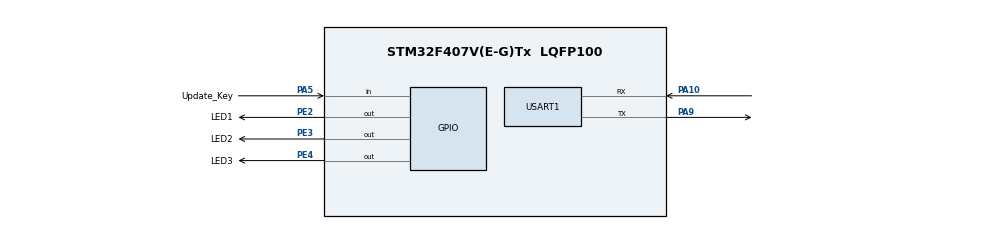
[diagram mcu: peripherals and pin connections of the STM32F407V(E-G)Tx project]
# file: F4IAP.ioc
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Mcu.Family=STM32F4
Mcu.Name=STM32F407V(E-G)Tx
Mcu.Package=LQFP100
NVIC.PriorityGroup=NVIC_PRIORITYGROUP_4
PA10.Mode=Asynchronous
PA10.Signal=USART1_RX
PA13.Mode=Serial_Wire
PA13.Signal=SYS_JTMS-SWDIO
PA14.Mode=Serial_Wire
PA14.Signal=SYS_JTCK-SWCLK
PA5.GPIO_Label=Update_Key
PA5.GPIO_PuPd=GPIO_PULLUP
PA5.Signal=GPIO_Input
PA9.Mode=Asynchronous
PA9.Signal=USART1_TX
PE2.GPIO_Label=LED1
PE2.GPIO_Speed=GPIO_SPEED_FREQ_HIGH
PE2.Signal=GPIO_Output
PE3.GPIO_Label=LED2
PE3.GPIO_Speed=GPIO_SPEED_FREQ_HIGH
PE3.Signal=GPIO_Output
PE4.GPIO_Label=LED3
PE4.GPIO_Speed=GPIO_SPEED_FREQ_HIGH
PE4.Signal=GPIO_Output
PH0-OSC_IN.Mode=HSE-External-Oscillator
PH0-OSC_IN.Signal=RCC_OSC_IN
PH1-OSC_OUT.Mode=HSE-External-Oscillator
PH1-OSC_OUT.Signal=RCC_OSC_OUT
ProjectManager.HeapSize=0x200
ProjectManager.StackSize=0x400
ProjectManager.TargetToolchain=MDK-ARM V5
RCC.48MHZClocksFreq_Value=84000000
RCC.AHBFreq_Value=168000000
RCC.APB1CLKDivider=RCC_HCLK_DIV4
RCC.APB1Freq_Value=42000000
RCC.APB1TimFreq_Value=84000000
RCC.APB2CLKDivider=RCC_HCLK_DIV2
RCC.APB2Freq_Value=84000000
RCC.APB2TimFreq_Value=168000000
RCC.CortexFreq_Value=168000000
RCC.HCLKFreq_Value=168000000
RCC.HSE_VALUE=25000000
RCC.HSI_VALUE=16000000
RCC.LSE_VALUE=32768
RCC.PLLM=25
RCC.PLLN=336
RCC.PLLSourceVirtual=RCC_PLLSOURCE_HSE
RCC.SYSCLKFreq_VALUE=168000000
RCC.SYSCLKSource=RCC_SYSCLKSOURCE_PLLCLK
RCC.VCOOutputFreq_Value=336000000
USART1.VirtualMode=VM_ASYNC
board=custom

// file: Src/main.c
/* USER CODE BEGIN Header */
/**
  ******************************************************************************
  * @file           : main.c
  * @brief          : Main program body
  ******************************************************************************
  ** This notice applies to any and all portions of this file
  * that are not between comment pairs USER CODE BEGIN and
  * USER CODE END. Other portions of this file, whether
  * inserted by the user or by software development tools
  * are owned by their respective copyright owners.
  *
  * COPYRIGHT(c) 2019 STMicroelectronics
  *
  * Redistribution and use in source and binary forms, with or without modification,
  * are permitted provided that the following conditions are met:
  *   1. Redistributions of source code must retain the above copyright notice,
  *      this list of conditions and the following disclaimer.
  *   2. Redistributions in binary form must reproduce the above copyright notice,
  *      this list of conditions and the following disclaimer in the documentation
  *      and/or other materials provided with the distribution.
  *   3. Neither the name of STMicroelectronics nor the names of its contributors
  *      may be used to endorse or promote products derived from this software
  *      without specific prior written permission.
  *
  * THIS SOFTWARE IS PROVIDED BY THE COPYRIGHT HOLDERS AND CONTRIBUTORS "AS IS"
  * AND ANY EXPRESS OR IMPLIED WARRANTIES, INCLUDING, BUT NOT LIMITED TO, THE
  * IMPLIED WARRANTIES OF MERCHANTABILITY AND FITNESS FOR A PARTICULAR PURPOSE ARE
  * DISCLAIMED. IN NO EVENT SHALL THE COPYRIGHT HOLDER OR CONTRIBUTORS BE LIABLE
  * FOR ANY DIRECT, INDIRECT, INCIDENTAL, SPECIAL, EXEMPLARY, OR CONSEQUENTIAL
  * DAMAGES (INCLUDING, BUT NOT LIMITED TO, PROCUREMENT OF SUBSTITUTE GOODS OR
  * SERVICES; LOSS OF USE, DATA, OR PROFITS; OR BUSINESS INTERRUPTION) HOWEVER
  * CAUSED AND ON ANY THEORY OF LIABILITY, WHETHER IN CONTRACT, STRICT LIABILITY,
  * OR TORT (INCLUDING NEGLIGENCE OR OTHERWISE) ARISING IN ANY WAY OUT OF THE USE
  * OF THIS SOFTWARE, EVEN IF ADVISED OF THE POSSIBILITY OF SUCH DAMAGE.
  *
  ******************************************************************************
  */
/* USER CODE END Header */

#include "main.h"
#include "usart.h"
#include "gpio.h"

/* USER CODE BEGIN Includes */
#include "menu.h"
/* USER CODE END Includes */

/* USER CODE BEGIN PD */
extern pFunction JumpToApplication;
extern uint32_t JumpAddress;
/* USER CODE END PD */

void SystemClock_Config(void);

int main(void)
{
  /* USER CODE BEGIN 1 */
	uint32_t tickstart = 0U;
	uint32_t Timeout = 30000;
  /* USER CODE END 1 */

  /* MCU Configuration--------------------------------------------------------*/

  /* Reset of all peripherals, Initializes the Flash interface and the Systick. */
  HAL_Init();

  /* Configure the system clock */
  SystemClock_Config();

  /* Initialize all configured peripherals */
  MX_GPIO_Init();
  MX_USART1_UART_Init();
  /* USER CODE BEGIN 2 */
	tickstart = HAL_GetTick();
	while((HAL_GetTick() - tickstart ) < Timeout)
	{
		if(HAL_GPIO_ReadPin(Update_Key_GPIO_Port,Update_Key_Pin) == 0)
		{
			Main_Menu();
		}
	}
	/* Test if user code is programmed starting from address "APPLICATION_ADDRESS" */
    if (((*(__IO uint32_t*)APPLICATION_ADDRESS) & 0x2FFE0000 ) == 0x20000000)
    {
      /* Jump to user application */
      JumpAddress = *(__IO uint32_t*) (APPLICATION_ADDRESS + 4);
      JumpToApplication = (pFunction) JumpAddress;
      /* Initialize user application's Stack Pointer */
      __set_MSP(*(__IO uint32_t*) APPLICATION_ADDRESS);
      JumpToApplication();
    }
  /* USER CODE END 2 */

  /* Infinite loop */
  while (1)
  {

  }
}

void SystemClock_Config(void)
{

  RCC_OscInitTypeDef RCC_OscInitStruct;
  RCC_ClkInitTypeDef RCC_ClkInitStruct;
  RCC_PeriphCLKInitTypeDef PeriphClkInitStruct;

    /**Configure the main internal regulator output voltage
    */
  __HAL_RCC_PWR_CLK_ENABLE();

  __HAL_PWR_VOLTAGESCALING_CONFIG(PWR_REGULATOR_VOLTAGE_SCALE1);

    /**Initializes the CPU, AHB and APB busses clocks
    */
  RCC_OscInitStruct.OscillatorType = RCC_OSCILLATORTYPE_HSE|RCC_OSCILLATORTYPE_LSE;
  RCC_OscInitStruct.HSEState = RCC_HSE_ON;
  RCC_OscInitStruct.LSEState = RCC_LSE_ON;
  RCC_OscInitStruct.PLL.PLLState = RCC_PLL_ON;
  RCC_OscInitStruct.PLL.PLLSource = RCC_PLLSOURCE_HSE;
  RCC_OscInitStruct.PLL.PLLM = 8;
  RCC_OscInitStruct.PLL.PLLN = 336;
  RCC_OscInitStruct.PLL.PLLP = RCC_PLLP_DIV2;
  RCC_OscInitStruct.PLL.PLLQ = 7;
  if (HAL_RCC_OscConfig(&RCC_OscInitStruct) != HAL_OK)
  {
    //_Error_Handler(__FILE__, __LINE__);
  }

    /**Initializes the CPU, AHB and APB busses clocks
    */
  RCC_ClkInitStruct.ClockType = RCC_CLOCKTYPE_HCLK|RCC_CLOCKTYPE_SYSCLK
                              |RCC_CLOCKTYPE_PCLK1|RCC_CLOCKTYPE_PCLK2;
  RCC_ClkInitStruct.SYSCLKSource = RCC_SYSCLKSOURCE_PLLCLK;
  RCC_ClkInitStruct.AHBCLKDivider = RCC_SYSCLK_DIV1;
  RCC_ClkInitStruct.APB1CLKDivider = RCC_HCLK_DIV4;
  RCC_ClkInitStruct.APB2CLKDivider = RCC_HCLK_DIV2;

  if (HAL_RCC_ClockConfig(&RCC_ClkInitStruct, FLASH_LATENCY_5) != HAL_OK)
  {
    //_Error_Handler(__FILE__, __LINE__);
  }

  PeriphClkInitStruct.PeriphClockSelection = RCC_PERIPHCLK_RTC;
  PeriphClkInitStruct.RTCClockSelection = RCC_RTCCLKSOURCE_LSE;
  if (HAL_RCCEx_PeriphCLKConfig(&PeriphClkInitStruct) != HAL_OK)
  {
   // _Error_Handler(__FILE__, __LINE__);
  }

    /**Configure the Systick interrupt time
    */
  HAL_SYSTICK_Config(HAL_RCC_GetHCLKFreq()/1000);

    /**Configure the Systick
    */
  HAL_SYSTICK_CLKSourceConfig(SYSTICK_CLKSOURCE_HCLK);

  /* SysTick_IRQn interrupt configuration */
  HAL_NVIC_SetPriority(SysTick_IRQn, 0, 0);
}

void Error_Handler(void)
{
}

/************************ (C) COPYRIGHT STMicroelectronics *****END OF FILE****/
